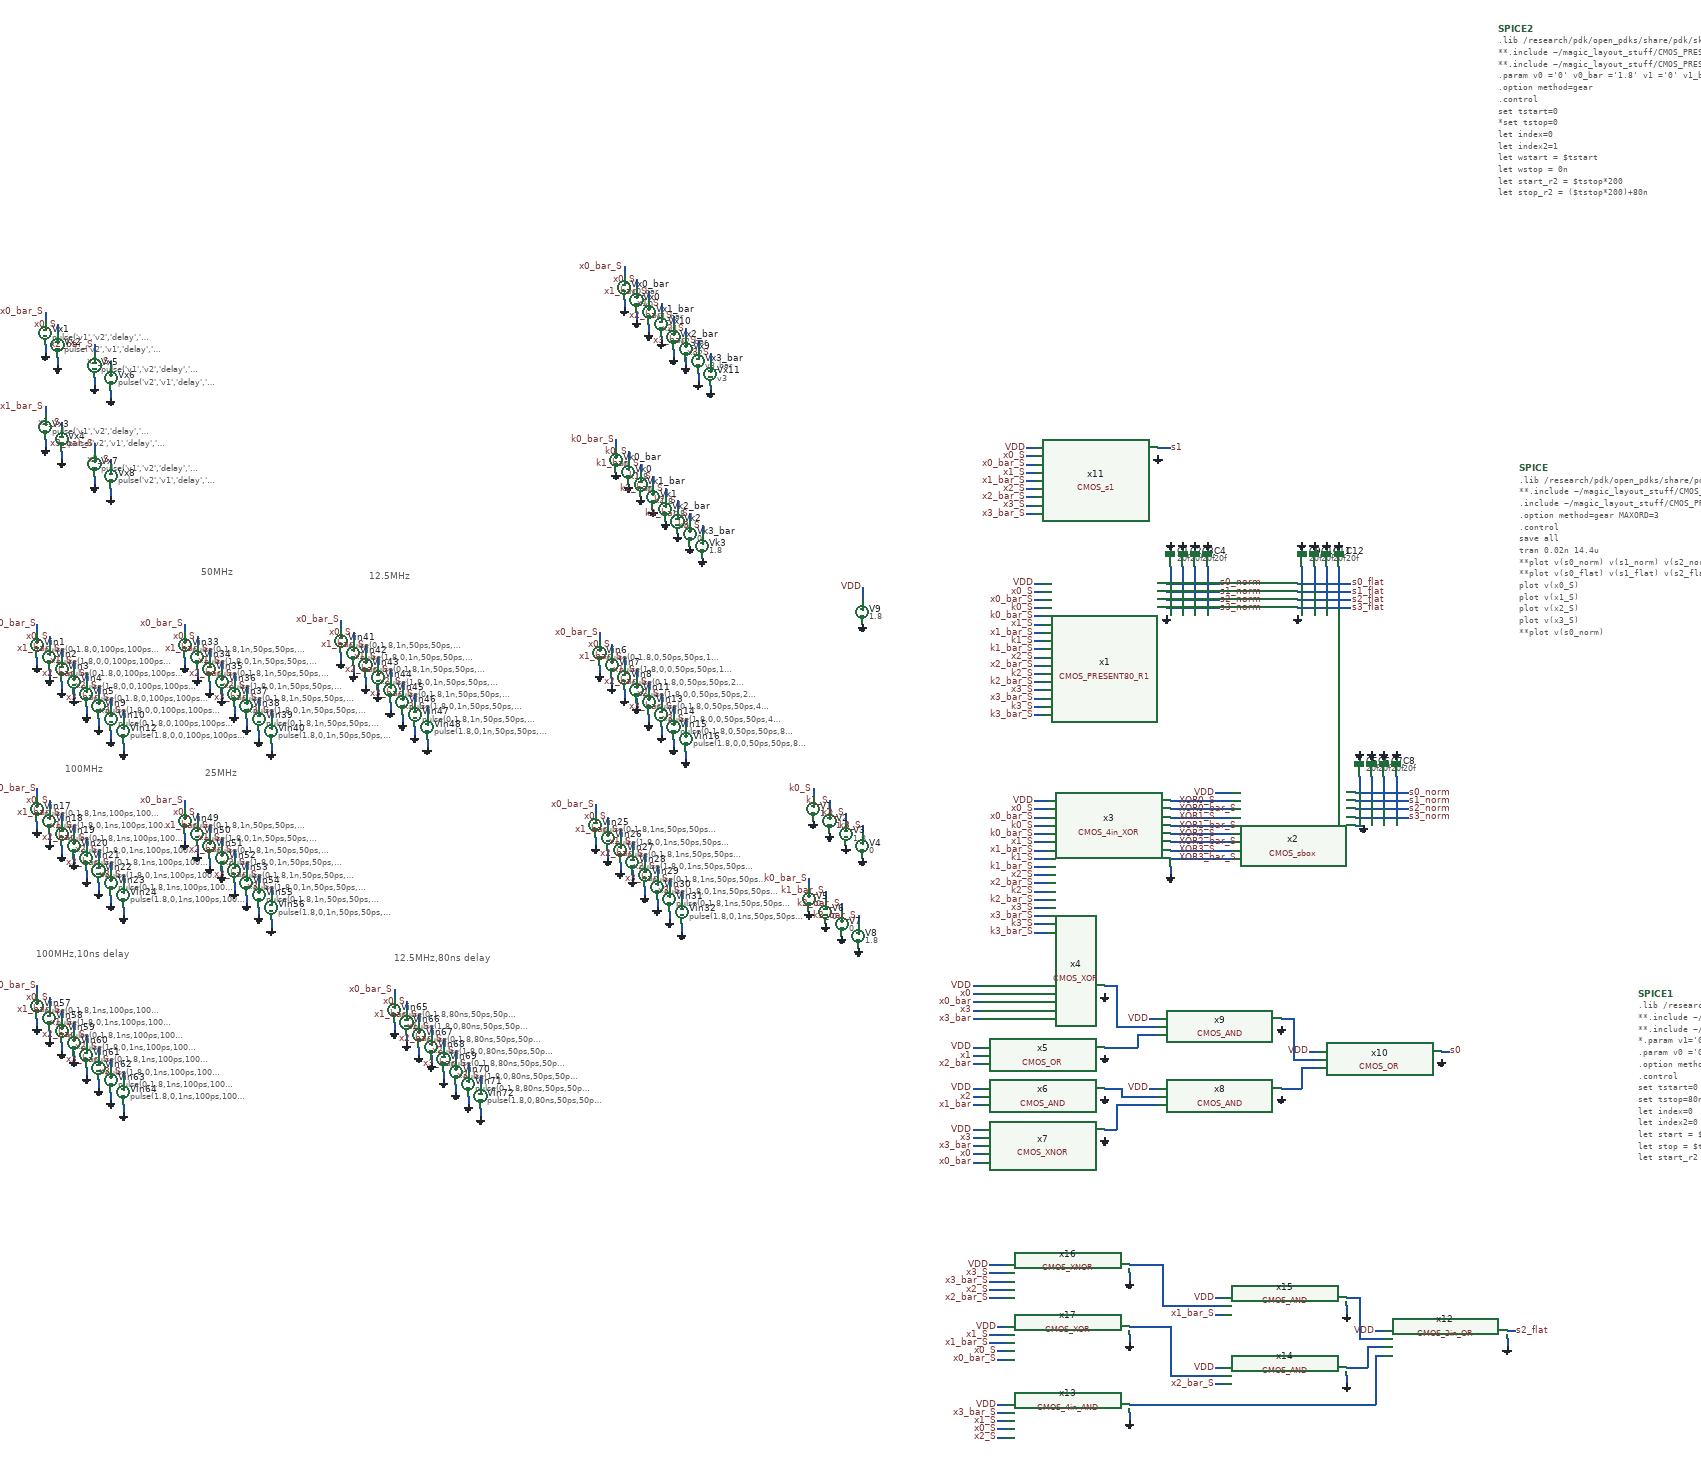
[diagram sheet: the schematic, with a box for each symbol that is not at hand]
v {xschem version=3.0.0 file_version=1.2 }
G {}
K {}
V {}
S {}
E {}
T {50MHz} -530 -1190 0 0 0.4 0.4 {}
T {25MHz} -520 -700 0 0 0.4 0.4 {}
T {12.5MHz} -120 -1180 0 0 0.4 0.4 {}
T {100MHz} -860 -710 0 0 0.4 0.4 {}
T {100MHz,10ns delay} -930 -260 0 0 0.4 0.4 {}
T {12.5MHz,80ns delay} -60 -250 0 0 0.4 0.4 {}
N 1820 -1150 1840 -1150 { lab=s0_norm}
N 1820 -1130 1840 -1130 { lab=s1_norm}
N 1820 -1110 1840 -1110 { lab=s2_norm}
N 1820 -1090 1840 -1090 { lab=s3_norm}
N 1500 -1130 1520 -1130 { lab=x0_S}
N 1500 -1110 1520 -1110 { lab=x0_bar_S}
N 1500 -890 1520 -890 { lab=x3_S}
N 1500 -870 1520 -870 { lab=x3_bar_S}
N 1500 -1050 1520 -1050 { lab=x1_S}
N 1500 -1030 1520 -1030 { lab=x1_bar_S}
N 1500 -950 1520 -950 { lab=x2_bar_S}
N 1500 -970 1520 -970 { lab=x2_S}
N 1500 -1090 1520 -1090 { lab=k0_S}
N 1500 -1070 1520 -1070 { lab=k0_bar_S}
N 1500 -1010 1520 -1010 { lab=k1_S}
N 1500 -990 1520 -990 { lab=k1_bar_S}
N 1500 -930 1520 -930 { lab=k2_S}
N 1500 -910 1520 -910 { lab=k2_bar_S}
N 1500 -850 1520 -850 { lab=k3_S}
N 1500 -830 1520 -830 { lab=k3_bar_S}
N 1500 -1150 1520 -1150 { lab=VDD}
N 1830 -1190 1830 -1150 { lab=s0_norm}
N 1840 -1150 1910 -1150 { lab=s0_norm}
N 1840 -1130 1910 -1130 { lab=s1_norm}
N 1840 -1110 1910 -1110 { lab=s2_norm}
N 1840 -1090 1910 -1090 { lab=s3_norm}
N 1910 -1150 1950 -1150 { lab=s0_norm}
N 1910 -1130 1950 -1130 { lab=s1_norm}
N 1910 -1110 1950 -1110 { lab=s2_norm}
N 1910 -1090 1950 -1090 { lab=s3_norm}
N 1860 -1190 1860 -1130 { lab=s1_norm}
N 1890 -1190 1890 -1110 { lab=s2_norm}
N 1920 -1190 1920 -1090 { lab=s3_norm}
N 1830 -620 1980 -620 { lab=#net1}
N 1830 -600 1980 -600 { lab=#net2}
N 1830 -580 1980 -580 { lab=#net3}
N 1830 -560 1980 -560 { lab=#net4}
N 1830 -540 1980 -540 { lab=#net5}
N 1830 -520 1980 -520 { lab=#net6}
N 1830 -500 1980 -500 { lab=#net7}
N 1830 -480 1980 -480 { lab=#net8}
N 1500 -600 1530 -600 { lab=x0_S}
N 1500 -580 1530 -580 { lab=x0_bar_S}
N 1500 -560 1530 -560 { lab=k0_S}
N 1500 -520 1530 -520 { lab=x1_S}
N 1500 -540 1530 -540 { lab=k0_bar_S}
N 1500 -500 1530 -500 { lab=x1_bar_S}
N 1500 -480 1530 -480 { lab=k1_S}
N 1500 -460 1530 -460 { lab=k1_bar_S}
N 1500 -440 1530 -440 { lab=x2_S}
N 1500 -420 1530 -420 { lab=x2_bar_S}
N 1500 -400 1530 -400 { lab=k2_S}
N 1500 -380 1530 -380 { lab=k2_bar_S}
N 1500 -360 1530 -360 { lab=x3_S}
N 1500 -340 1530 -340 { lab=x3_bar_S}
N 1500 -320 1530 -320 { lab=k3_S}
N 1500 -300 1530 -300 { lab=k3_bar_S}
N 2280 -560 2300 -560 { lab=GND}
N 1830 -460 1830 -440 { lab=GND}
N 1500 -620 1530 -620 { lab=VDD}
N 1940 -640 1980 -640 { lab=VDD}
N 2280 -640 2300 -640 { lab=s0_norm}
N 2280 -620 2300 -620 { lab=s1_norm}
N 2280 -600 2300 -600 { lab=s2_norm}
N 2280 -580 2300 -580 { lab=s3_norm}
N 2290 -680 2290 -640 { lab=s0_norm}
N 2300 -640 2370 -640 { lab=s0_norm}
N 2300 -620 2370 -620 { lab=s1_norm}
N 2300 -600 2370 -600 { lab=s2_norm}
N 2300 -580 2370 -580 { lab=s3_norm}
N 2370 -640 2410 -640 { lab=s0_norm}
N 2370 -620 2410 -620 { lab=s1_norm}
N 2370 -600 2410 -600 { lab=s2_norm}
N 2370 -580 2410 -580 { lab=s3_norm}
N 2320 -680 2320 -620 { lab=s1_norm}
N 2350 -680 2350 -600 { lab=s2_norm}
N 2380 -680 2380 -580 { lab=s3_norm}
N 440 -1030 440 -1010 { lab=x0_bar_S}
N 440 -950 440 -930 { lab=GND}
N 470 -1000 470 -980 { lab=x0_S}
N 470 -920 470 -900 { lab=GND}
N 500 -970 500 -950 { lab=x1_bar_S}
N 500 -890 500 -870 { lab=GND}
N 530 -940 530 -920 { lab=x1_S}
N 530 -870 530 -850 { lab=GND}
N 560 -910 560 -890 { lab=x2_bar_S}
N 560 -830 560 -810 { lab=GND}
N 590 -880 590 -860 { lab=x2_S}
N 590 -800 590 -780 { lab=GND}
N 620 -850 620 -830 { lab=x3_bar_S}
N 620 -770 620 -750 { lab=GND}
N 650 -820 650 -800 { lab=x3_S}
N 650 -740 650 -720 { lab=GND}
N 960 -650 960 -630 { lab=k0_S}
N 1040 -590 1040 -570 { lab=k2_S}
N 1080 -560 1080 -540 { lab=k3_S}
N 1000 -620 1000 -600 { lab=k1_S}
N 950 -430 950 -410 { lab=k0_bar_S}
N 1030 -370 1030 -350 { lab=k2_bar_S}
N 1070 -340 1070 -320 { lab=k3_bar_S}
N 990 -400 990 -380 { lab=k1_bar_S}
N 1080 -1140 1080 -1110 { lab=VDD}
N -930 -1050 -930 -1030 { lab=x0_bar_S}
N -930 -970 -930 -950 { lab=GND}
N -900 -1020 -900 -1000 { lab=x0_S}
N -900 -940 -900 -920 { lab=GND}
N -870 -990 -870 -970 { lab=x1_bar_S}
N -870 -910 -870 -890 { lab=GND}
N -840 -960 -840 -940 { lab=x1_S}
N -840 -890 -840 -870 { lab=GND}
N -810 -930 -810 -910 { lab=x2_bar_S}
N -810 -850 -810 -830 { lab=GND}
N -780 -900 -780 -880 { lab=x2_S}
N -780 -820 -780 -800 { lab=GND}
N -750 -870 -750 -850 { lab=x3_bar_S}
N -750 -790 -750 -770 { lab=GND}
N -720 -840 -720 -820 { lab=x3_S}
N -720 -760 -720 -740 { lab=GND}
N 1350 -150 1370 -150 { lab=x0}
N 1350 -130 1370 -130 { lab=x0_bar}
N 1350 -110 1370 -110 { lab=x3}
N 1350 -90 1370 -90 { lab=x3_bar}
N 1350 -20 1370 -20 { lab=VDD}
N 1350 0 1370 0 { lab=x1}
N 1350 20 1370 20 { lab=x2_bar}
N 1350 100 1370 100 { lab=x2}
N 1350 120 1370 120 { lab=x1_bar}
N 1350 -170 1370 -170 { lab=VDD}
N 1350 80 1370 80 { lab=VDD}
N 1350 200 1370 200 { lab=x3}
N 1350 220 1370 220 { lab=x3_bar}
N 1350 180 1370 180 { lab=VDD}
N 1350 240 1370 240 { lab=x0}
N 1350 260 1370 260 { lab=x0_bar}
N 1670 -170 1700 -170 { lab=#net1}
N 1700 -170 1700 -70 { lab=#net1}
N 1700 -70 1800 -70 { lab=#net1}
N 1670 -20 1750 -20 { lab=#net2}
N 1670 80 1710 80 { lab=#net3}
N 1710 80 1710 100 { lab=#net3}
N 1710 100 1800 100 { lab=#net3}
N 1670 180 1700 180 { lab=#net4}
N 1700 120 1700 180 { lab=#net4}
N 1700 120 1800 120 { lab=#net4}
N 1750 -50 1750 -20 { lab=#net2}
N 1750 -50 1800 -50 { lab=#net2}
N 1780 80 1800 80 { lab=VDD}
N 1780 -90 1800 -90 { lab=VDD}
N 2100 80 2150 80 { lab=#net5}
N 2150 30 2150 80 { lab=#net5}
N 2150 30 2190 30 { lab=#net5}
N 2100 -90 2130 -90 { lab=#net6}
N 2130 -90 2130 10 { lab=#net6}
N 2130 10 2190 10 { lab=#net6}
N 2490 -10 2510 -10 { lab=s0}
N 2170 -10 2190 -10 { lab=VDD}
N -930 -650 -930 -630 { lab=x0_bar_S}
N -930 -570 -930 -550 { lab=GND}
N -900 -620 -900 -600 { lab=x0_S}
N -900 -540 -900 -520 { lab=GND}
N -870 -590 -870 -570 { lab=x1_bar_S}
N -870 -510 -870 -490 { lab=GND}
N -840 -560 -840 -540 { lab=x1_S}
N -840 -490 -840 -470 { lab=GND}
N -810 -530 -810 -510 { lab=x2_bar_S}
N -810 -450 -810 -430 { lab=GND}
N -780 -500 -780 -480 { lab=x2_S}
N -780 -420 -780 -400 { lab=GND}
N -750 -470 -750 -450 { lab=x3_bar_S}
N -750 -390 -750 -370 { lab=GND}
N -720 -440 -720 -420 { lab=x3_S}
N -720 -360 -720 -340 { lab=GND}
N 430 -610 430 -590 { lab=x0_bar_S}
N 430 -530 430 -510 { lab=GND}
N 460 -580 460 -560 { lab=x0_S}
N 460 -500 460 -480 { lab=GND}
N 490 -550 490 -530 { lab=x1_bar_S}
N 490 -470 490 -450 { lab=GND}
N 520 -520 520 -500 { lab=x1_S}
N 520 -450 520 -430 { lab=GND}
N 550 -490 550 -470 { lab=x2_bar_S}
N 550 -410 550 -390 { lab=GND}
N 580 -460 580 -440 { lab=x2_S}
N 580 -380 580 -360 { lab=GND}
N 610 -430 610 -410 { lab=x3_bar_S}
N 610 -350 610 -330 { lab=GND}
N 640 -400 640 -380 { lab=x3_S}
N 640 -320 640 -300 { lab=GND}
N 1480 -1460 1500 -1460 { lab=x0_S}
N 1480 -1440 1500 -1440 { lab=x0_bar_S}
N 1480 -1340 1500 -1340 { lab=x3_S}
N 1480 -1320 1500 -1320 { lab=x3_bar_S}
N 1480 -1420 1500 -1420 { lab=x1_S}
N 1480 -1400 1500 -1400 { lab=x1_bar_S}
N 1480 -1360 1500 -1360 { lab=x2_bar_S}
N 1480 -1380 1500 -1380 { lab=x2_S}
N 1480 -1480 1500 -1480 { lab=VDD}
N 1800 -1480 1830 -1480 { lab=s1}
N 1390 530 1410 530 { lab=x3_S}
N 1390 550 1410 550 { lab=x3_bar_S}
N 1390 680 1410 680 { lab=x1_S}
N 1390 590 1410 590 { lab=x2_bar_S}
N 1390 570 1410 570 { lab=x2_S}
N 1390 700 1410 700 { lab=x1_bar_S}
N 1410 530 1430 530 { lab=x3_S}
N 1410 550 1430 550 { lab=x3_bar_S}
N 1410 720 1430 720 { lab=x0_S}
N 1410 740 1430 740 { lab=x0_bar_S}
N 1410 660 1430 660 { lab=VDD}
N 1410 680 1430 680 { lab=x1_S}
N 1410 590 1430 590 { lab=x2_bar_S}
N 1410 570 1430 570 { lab=x2_S}
N 1410 700 1430 700 { lab=x1_bar_S}
N 1410 510 1430 510 { lab=VDD}
N 1410 870 1430 870 { lab=x3_bar_S}
N 1410 850 1430 850 { lab=VDD}
N 1410 910 1430 910 { lab=x0_S}
N 1940 760 1960 760 { lab=VDD}
N 1940 590 1960 590 { lab=VDD}
N 2260 760 2310 760 { lab=#net1}
N 2310 710 2310 760 { lab=#net1}
N 2310 710 2350 710 { lab=#net1}
N 2260 590 2290 590 { lab=#net2}
N 2290 590 2290 690 { lab=#net2}
N 2290 690 2350 690 { lab=#net2}
N 2650 670 2670 670 { lab=s2_flat}
N 2330 670 2350 670 { lab=VDD}
N 1410 890 1430 890 { lab=x1_S}
N 1730 510 1810 510 { lab=#net3}
N 1810 510 1810 610 { lab=#net3}
N 1810 610 1960 610 { lab=#net3}
N 1940 630 1960 630 { lab=x1_bar_S}
N 1730 660 1830 660 { lab=#net4}
N 1830 660 1830 780 { lab=#net4}
N 1830 780 1960 780 { lab=#net4}
N 1940 800 1960 800 { lab=x2_bar_S}
N 1730 850 2330 850 { lab=#net5}
N 2330 730 2330 850 { lab=#net5}
N 2330 730 2350 730 { lab=#net5}
N 1410 930 1430 930 { lab=x2_S}
N 1730 680 1730 700 { lab=GND}
N 2650 690 2650 710 { lab=GND}
N 1730 530 1730 550 { lab=GND}
N 1730 870 1730 890 { lab=GND}
N 2260 610 2260 630 { lab=GND}
N 2260 780 2260 800 { lab=GND}
N 1390 510 1410 510 { lab=VDD}
N -570 -1050 -570 -1030 { lab=x0_bar_S}
N -570 -970 -570 -950 { lab=GND}
N -540 -1020 -540 -1000 { lab=x0_S}
N -540 -940 -540 -920 { lab=GND}
N -510 -990 -510 -970 { lab=x1_bar_S}
N -510 -910 -510 -890 { lab=GND}
N -480 -960 -480 -940 { lab=x1_S}
N -480 -890 -480 -870 { lab=GND}
N -450 -930 -450 -910 { lab=x2_bar_S}
N -450 -850 -450 -830 { lab=GND}
N -420 -900 -420 -880 { lab=x2_S}
N -420 -820 -420 -800 { lab=GND}
N -390 -870 -390 -850 { lab=x3_bar_S}
N -390 -790 -390 -770 { lab=GND}
N -360 -840 -360 -820 { lab=x3_S}
N -360 -760 -360 -740 { lab=GND}
N -190 -1060 -190 -1040 { lab=x0_bar_S}
N -190 -980 -190 -960 { lab=GND}
N -160 -1030 -160 -1010 { lab=x0_S}
N -160 -950 -160 -930 { lab=GND}
N -130 -1000 -130 -980 { lab=x1_bar_S}
N -130 -920 -130 -900 { lab=GND}
N -100 -970 -100 -950 { lab=x1_S}
N -100 -900 -100 -880 { lab=GND}
N -70 -940 -70 -920 { lab=x2_bar_S}
N -70 -860 -70 -840 { lab=GND}
N -40 -910 -40 -890 { lab=x2_S}
N -40 -830 -40 -810 { lab=GND}
N -10 -880 -10 -860 { lab=x3_bar_S}
N -10 -800 -10 -780 { lab=GND}
N 20 -850 20 -830 { lab=x3_S}
N 20 -770 20 -750 { lab=GND}
N -570 -620 -570 -600 { lab=x0_bar_S}
N -570 -540 -570 -520 { lab=GND}
N -540 -590 -540 -570 { lab=x0_S}
N -540 -510 -540 -490 { lab=GND}
N -510 -560 -510 -540 { lab=x1_bar_S}
N -510 -480 -510 -460 { lab=GND}
N -480 -530 -480 -510 { lab=x1_S}
N -480 -460 -480 -440 { lab=GND}
N -450 -500 -450 -480 { lab=x2_bar_S}
N -450 -420 -450 -400 { lab=GND}
N -420 -470 -420 -450 { lab=x2_S}
N -420 -390 -420 -370 { lab=GND}
N -390 -440 -390 -420 { lab=x3_bar_S}
N -390 -360 -390 -340 { lab=GND}
N -360 -410 -360 -390 { lab=x3_S}
N -360 -330 -360 -310 { lab=GND}
N -930 -170 -930 -150 { lab=x0_bar_S}
N -930 -90 -930 -70 { lab=GND}
N -900 -140 -900 -120 { lab=x0_S}
N -900 -60 -900 -40 { lab=GND}
N -870 -110 -870 -90 { lab=x1_bar_S}
N -870 -30 -870 -10 { lab=GND}
N -840 -80 -840 -60 { lab=x1_S}
N -840 -10 -840 10 { lab=GND}
N -810 -50 -810 -30 { lab=x2_bar_S}
N -810 30 -810 50 { lab=GND}
N -780 -20 -780 0 { lab=x2_S}
N -780 60 -780 80 { lab=GND}
N -750 10 -750 30 { lab=x3_bar_S}
N -750 90 -750 110 { lab=GND}
N -720 40 -720 60 { lab=x3_S}
N -720 120 -720 140 { lab=GND}
N -60 -160 -60 -140 { lab=x0_bar_S}
N -60 -80 -60 -60 { lab=GND}
N -30 -130 -30 -110 { lab=x0_S}
N -30 -50 -30 -30 { lab=GND}
N 0 -100 0 -80 { lab=x1_bar_S}
N 0 -20 0 0 { lab=GND}
N 30 -70 30 -50 { lab=x1_S}
N 30 0 30 20 { lab=GND}
N 60 -40 60 -20 { lab=x2_bar_S}
N 60 40 60 60 { lab=GND}
N 90 -10 90 10 { lab=x2_S}
N 90 70 90 90 { lab=GND}
N 120 20 120 40 { lab=x3_bar_S}
N 120 100 120 120 { lab=GND}
N 150 50 150 70 { lab=x3_S}
N 150 130 150 150 { lab=GND}
N 2140 -1150 2160 -1150 { lab=s0_flat}
N 2140 -1130 2160 -1130 { lab=s1_flat}
N 2140 -1110 2160 -1110 { lab=s2_flat}
N 2140 -1090 2160 -1090 { lab=s3_flat}
N 2150 -1190 2150 -1150 { lab=s0_flat}
N 2160 -1150 2230 -1150 { lab=s0_flat}
N 2160 -1130 2230 -1130 { lab=s1_flat}
N 2160 -1110 2230 -1110 { lab=s2_flat}
N 2160 -1090 2230 -1090 { lab=s3_flat}
N 2230 -1150 2270 -1150 { lab=s0_flat}
N 2230 -1130 2270 -1130 { lab=s1_flat}
N 2230 -1110 2270 -1110 { lab=s2_flat}
N 2230 -1090 2270 -1090 { lab=s3_flat}
N 2180 -1190 2180 -1130 { lab=s1_flat}
N 2210 -1190 2210 -1110 { lab=s2_flat}
N 2240 -1190 2240 -1090 { lab=s3_flat}
N -910 -1580 -910 -1560 { lab=x1_bar_S}
N -870 -1540 -870 -1520 { lab=x1_S}
N -910 -1810 -910 -1790 { lab=x0_bar_S}
N -910 -1730 -910 -1710 { lab=GND}
N -880 -1780 -880 -1760 { lab=x0_S}
N -880 -1700 -880 -1680 { lab=GND}
N -910 -1500 -910 -1480 { lab=GND}
N -870 -1470 -870 -1450 { lab=GND}
N -790 -1730 -790 -1710 { lab=x2_bar_S}
N -750 -1690 -750 -1670 { lab=x2_S}
N -790 -1650 -790 -1630 { lab=GND}
N -750 -1620 -750 -1600 { lab=GND}
N -790 -1490 -790 -1470 { lab=x3_bar_S}
N -750 -1450 -750 -1430 { lab=x3_S}
N -790 -1410 -790 -1390 { lab=GND}
N -750 -1380 -750 -1360 { lab=GND}
N 510 -1470 510 -1450 { lab=k0_S}
N 630 -1350 630 -1330 { lab=k2_S}
N 690 -1290 690 -1270 { lab=k3_S}
N 570 -1410 570 -1390 { lab=k1_S}
N 480 -1500 480 -1480 { lab=k0_bar_S}
N 600 -1380 600 -1360 { lab=k2_bar_S}
N 660 -1320 660 -1300 { lab=k3_bar_S}
N 540 -1440 540 -1420 { lab=k1_bar_S}
N 560 -1860 560 -1840 { lab=x1_bar_S}
N 590 -1830 590 -1810 { lab=x1_S}
N 500 -1920 500 -1900 { lab=x0_bar_S}
N 500 -1840 500 -1820 { lab=GND}
N 530 -1890 530 -1870 { lab=x0_S}
N 530 -1810 530 -1790 { lab=GND}
N 560 -1780 560 -1760 { lab=GND}
N 620 -1800 620 -1780 { lab=x2_bar_S}
N 650 -1770 650 -1750 { lab=x2_S}
N 620 -1720 620 -1700 { lab=GND}
N 650 -1700 650 -1680 { lab=GND}
N 680 -1740 680 -1720 { lab=x3_bar_S}
N 710 -1710 710 -1690 { lab=x3_S}
N 680 -1660 680 -1640 { lab=GND}
N 590 -1750 590 -1740 { lab=GND}
N 710 -1630 710 -1620 { lab=GND}
C {CMOS_PRESENT80_R1.sym} 1670 -990 0 0 {name=x1}
C {devices/gnd.sym} 1820 -1070 0 0 {name=l314 lab=GND}
C {devices/lab_pin.sym} 1950 -1150 2 0 {name=l315 sig_type=std_logic lab=s0_norm}
C {devices/lab_pin.sym} 1950 -1130 2 0 {name=l317 sig_type=std_logic lab=s1_norm}
C {devices/lab_pin.sym} 1950 -1110 2 0 {name=l319 sig_type=std_logic lab=s2_norm}
C {devices/lab_pin.sym} 1950 -1090 2 0 {name=l321 sig_type=std_logic lab=s3_norm}
C {devices/lab_pin.sym} 1500 -1130 0 0 {name=l323 sig_type=std_logic lab=x0_S}
C {devices/lab_pin.sym} 1500 -1110 0 0 {name=l324 sig_type=std_logic lab=x0_bar_S}
C {devices/lab_pin.sym} 1500 -890 0 0 {name=l325 sig_type=std_logic lab=x3_S}
C {devices/lab_pin.sym} 1500 -870 0 0 {name=l326 sig_type=std_logic lab=x3_bar_S}
C {devices/lab_pin.sym} 1500 -1030 0 0 {name=l328 sig_type=std_logic lab=x1_bar_S}
C {devices/lab_pin.sym} 1500 -1050 0 0 {name=l329 sig_type=std_logic lab=x1_S}
C {devices/lab_pin.sym} 1500 -950 0 0 {name=l330 sig_type=std_logic lab=x2_bar_S}
C {devices/lab_pin.sym} 1500 -970 0 0 {name=l331 sig_type=std_logic lab=x2_S}
C {devices/lab_pin.sym} 1500 -1090 0 0 {name=l332 sig_type=std_logic lab=k0_S}
C {devices/lab_pin.sym} 1500 -1010 0 0 {name=l333 sig_type=std_logic lab=k1_S}
C {devices/lab_pin.sym} 1500 -930 0 0 {name=l334 sig_type=std_logic lab=k2_S}
C {devices/lab_pin.sym} 1500 -850 0 0 {name=l335 sig_type=std_logic lab=k3_S}
C {devices/lab_pin.sym} 1500 -1070 0 0 {name=l336 sig_type=std_logic lab=k0_bar_S}
C {devices/lab_pin.sym} 1500 -990 0 0 {name=l337 sig_type=std_logic lab=k1_bar_S}
C {devices/lab_pin.sym} 1500 -910 0 0 {name=l338 sig_type=std_logic lab=k2_bar_S}
C {devices/lab_pin.sym} 1500 -830 0 0 {name=l339 sig_type=std_logic lab=k3_bar_S}
C {devices/lab_pin.sym} 1500 -1150 0 0 {name=l1 sig_type=std_logic lab=VDD}
C {devices/capa.sym} 1830 -1220 2 0 {name=C1
m=1
value=20f
footprint=1206
device="ceramic capacitor"}
C {devices/gnd.sym} 1830 -1250 2 0 {name=l4 lab=GND}
C {devices/capa.sym} 1860 -1220 2 0 {name=C2
m=1
value=20f
footprint=1206
device="ceramic capacitor"}
C {devices/gnd.sym} 1860 -1250 2 0 {name=l5 lab=GND}
C {devices/capa.sym} 1890 -1220 2 0 {name=C3
m=1
value=20f
footprint=1206
device="ceramic capacitor"}
C {devices/gnd.sym} 1890 -1250 2 0 {name=l6 lab=GND}
C {devices/capa.sym} 1920 -1220 2 0 {name=C4
m=1
value=20f
footprint=1206
device="ceramic capacitor"}
C {devices/gnd.sym} 1920 -1250 2 0 {name=l7 lab=GND}
C {devices/lab_pin.sym} 1940 -640 0 0 {name=l8 sig_type=std_logic lab=VDD}
C {CMOS_sbox.sym} 2130 -560 0 0 {name=x2}
C {CMOS_4in_XOR.sym} 1680 -460 0 0 {name=x3}
C {devices/lab_pin.sym} 1500 -600 0 0 {name=l21 sig_type=std_logic lab=x0_S}
C {devices/lab_pin.sym} 1500 -580 0 0 {name=l22 sig_type=std_logic lab=x0_bar_S}
C {devices/lab_pin.sym} 1500 -360 0 0 {name=l25 sig_type=std_logic lab=x3_S}
C {devices/lab_pin.sym} 1500 -340 0 0 {name=l26 sig_type=std_logic lab=x3_bar_S}
C {devices/lab_pin.sym} 1500 -500 0 0 {name=l27 sig_type=std_logic lab=x1_bar_S}
C {devices/lab_pin.sym} 1500 -520 0 0 {name=l28 sig_type=std_logic lab=x1_S}
C {devices/lab_pin.sym} 1500 -420 0 0 {name=l29 sig_type=std_logic lab=x2_bar_S}
C {devices/lab_pin.sym} 1500 -440 0 0 {name=l30 sig_type=std_logic lab=x2_S}
C {devices/lab_pin.sym} 1500 -560 0 0 {name=l34 sig_type=std_logic lab=k0_S}
C {devices/lab_pin.sym} 1500 -480 0 0 {name=l35 sig_type=std_logic lab=k1_S}
C {devices/lab_pin.sym} 1500 -400 0 0 {name=l36 sig_type=std_logic lab=k2_S}
C {devices/lab_pin.sym} 1500 -320 0 0 {name=l37 sig_type=std_logic lab=k3_S}
C {devices/lab_pin.sym} 1500 -540 0 0 {name=l38 sig_type=std_logic lab=k0_bar_S}
C {devices/lab_pin.sym} 1500 -460 0 0 {name=l39 sig_type=std_logic lab=k1_bar_S}
C {devices/lab_pin.sym} 1500 -380 0 0 {name=l40 sig_type=std_logic lab=k2_bar_S}
C {devices/lab_pin.sym} 1500 -300 0 0 {name=l41 sig_type=std_logic lab=k3_bar_S}
C {devices/lab_pin.sym} 1500 -620 0 0 {name=l42 sig_type=std_logic lab=VDD}
C {devices/gnd.sym} 2300 -560 0 0 {name=l47 lab=GND}
C {devices/gnd.sym} 1830 -440 0 0 {name=l20 lab=GND}
C {devices/lab_pin.sym} 2410 -640 2 0 {name=l43 sig_type=std_logic lab=s0_norm}
C {devices/lab_pin.sym} 2410 -620 2 0 {name=l44 sig_type=std_logic lab=s1_norm}
C {devices/lab_pin.sym} 2410 -600 2 0 {name=l45 sig_type=std_logic lab=s2_norm}
C {devices/lab_pin.sym} 2410 -580 2 0 {name=l46 sig_type=std_logic lab=s3_norm}
C {devices/capa.sym} 2290 -710 2 0 {name=C5
m=1
value=20f
footprint=1206
device="ceramic capacitor"}
C {devices/gnd.sym} 2290 -740 2 0 {name=l48 lab=GND}
C {devices/capa.sym} 2320 -710 2 0 {name=C6
m=1
value=20f
footprint=1206
device="ceramic capacitor"}
C {devices/gnd.sym} 2320 -740 2 0 {name=l49 lab=GND}
C {devices/capa.sym} 2350 -710 2 0 {name=C7
m=1
value=20f
footprint=1206
device="ceramic capacitor"}
C {devices/gnd.sym} 2350 -740 2 0 {name=l50 lab=GND}
C {devices/capa.sym} 2380 -710 2 0 {name=C8
m=1
value=20f
footprint=1206
device="ceramic capacitor"}
C {devices/gnd.sym} 2380 -740 2 0 {name=l51 lab=GND}
C {devices/lab_pin.sym} 1850 -600 2 0 {name=l210 sig_type=std_logic lab=XOR0_bar_S}
C {devices/lab_pin.sym} 1850 -620 2 0 {name=l211 sig_type=std_logic lab=XOR0_S}
C {devices/lab_pin.sym} 1850 -560 2 0 {name=l222 sig_type=std_logic lab=XOR1_bar_S}
C {devices/lab_pin.sym} 1850 -580 2 0 {name=l223 sig_type=std_logic lab=XOR1_S}
C {devices/lab_pin.sym} 1850 -520 2 0 {name=l224 sig_type=std_logic lab=XOR2_bar_S}
C {devices/lab_pin.sym} 1850 -540 2 0 {name=l225 sig_type=std_logic lab=XOR2_S}
C {devices/lab_pin.sym} 1850 -480 2 0 {name=l226 sig_type=std_logic lab=XOR3_bar_S}
C {devices/lab_pin.sym} 1850 -500 2 0 {name=l227 sig_type=std_logic lab=XOR3_S}
C {devices/gnd.sym} 560 -810 0 0 {name=l102 lab=GND}
C {devices/lab_pin.sym} 590 -880 1 0 {name=l103 sig_type=std_logic lab=x2_S}
C {devices/lab_pin.sym} 620 -850 1 0 {name=l104 sig_type=std_logic lab=x3_bar_S}
C {devices/gnd.sym} 650 -720 0 0 {name=l105 lab=GND}
C {devices/gnd.sym} 620 -750 0 0 {name=l106 lab=GND}
C {devices/lab_pin.sym} 650 -820 1 0 {name=l107 sig_type=std_logic lab=x3_S}
C {devices/vsource.sym} 440 -980 0 0 {name=Vin6 value=pulse(0,1.8,0,50ps,50ps,100ns,200ns)}
C {devices/vsource.sym} 470 -950 0 0 {name=Vin7 value=pulse(1.8,0,0,50ps,50ps,100ns,200ns)}
C {devices/vsource.sym} 500 -920 0 0 {name=Vin8 value=pulse(0,1.8,0,50ps,50ps,200ns,400ns)}
C {devices/vsource.sym} 530 -890 0 0 {name=Vin11 value=pulse(1.8,0,0,50ps,50ps,200ns,400ns)}
C {devices/vsource.sym} 560 -860 0 0 {name=Vin13 value=pulse(0,1.8,0,50ps,50ps,400ns,800ns)}
C {devices/vsource.sym} 590 -830 0 0 {name=Vin14 value=pulse(1.8,0,0,50ps,50ps,400ns,800ns)}
C {devices/vsource.sym} 620 -800 0 0 {name=Vin15 value=pulse(0,1.8,0,50ps,50ps,800ns,1600ns)}
C {devices/vsource.sym} 650 -770 0 0 {name=Vin16 value=pulse(1.8,0,0,50ps,50ps,800ns,1600ns)}
C {devices/lab_pin.sym} 440 -1030 1 0 {name=l124 sig_type=std_logic lab=x0_bar_S}
C {devices/gnd.sym} 470 -900 0 0 {name=l125 lab=GND}
C {devices/gnd.sym} 440 -930 0 0 {name=l126 lab=GND}
C {devices/lab_pin.sym} 470 -1000 1 0 {name=l127 sig_type=std_logic lab=x0_S}
C {devices/lab_pin.sym} 500 -970 1 0 {name=l128 sig_type=std_logic lab=x1_bar_S}
C {devices/gnd.sym} 530 -850 0 0 {name=l129 lab=GND}
C {devices/gnd.sym} 500 -870 0 0 {name=l130 lab=GND}
C {devices/lab_pin.sym} 530 -940 1 0 {name=l131 sig_type=std_logic lab=x1_S}
C {devices/lab_pin.sym} 560 -910 1 0 {name=l132 sig_type=std_logic lab=x2_bar_S}
C {devices/gnd.sym} 590 -780 0 0 {name=l133 lab=GND}
C {devices/vsource.sym} 960 -600 0 0 {name=V1 value=1.8}
C {devices/vsource.sym} 1000 -570 0 0 {name=V2 value=1.8}
C {devices/vsource.sym} 1040 -540 0 0 {name=V3 value=1.8}
C {devices/vsource.sym} 1080 -510 0 0 {name=V4 value=0}
C {devices/gnd.sym} 960 -570 0 0 {name=l9 lab=GND}
C {devices/gnd.sym} 1000 -540 0 0 {name=l10 lab=GND}
C {devices/gnd.sym} 1040 -510 0 0 {name=l11 lab=GND}
C {devices/gnd.sym} 1080 -480 0 0 {name=l12 lab=GND}
C {devices/lab_pin.sym} 960 -650 1 0 {name=l13 sig_type=std_logic lab=k0_S}
C {devices/lab_pin.sym} 1000 -620 1 0 {name=l14 sig_type=std_logic lab=k1_S}
C {devices/lab_pin.sym} 1040 -590 1 0 {name=l15 sig_type=std_logic lab=k2_S}
C {devices/lab_pin.sym} 1080 -560 1 0 {name=l16 sig_type=std_logic lab=k3_S}
C {devices/vsource.sym} 950 -380 0 0 {name=V5 value=0}
C {devices/vsource.sym} 990 -350 0 0 {name=V6 value=0}
C {devices/vsource.sym} 1030 -320 0 0 {name=V7 value=0}
C {devices/vsource.sym} 1070 -290 0 0 {name=V8 value=1.8}
C {devices/gnd.sym} 950 -350 0 0 {name=l17 lab=GND}
C {devices/gnd.sym} 990 -320 0 0 {name=l18 lab=GND}
C {devices/gnd.sym} 1030 -290 0 0 {name=l19 lab=GND}
C {devices/gnd.sym} 1070 -260 0 0 {name=l23 lab=GND}
C {devices/lab_pin.sym} 950 -430 1 0 {name=l24 sig_type=std_logic lab=k0_bar_S}
C {devices/lab_pin.sym} 990 -400 1 0 {name=l31 sig_type=std_logic lab=k1_bar_S}
C {devices/lab_pin.sym} 1030 -370 1 0 {name=l32 sig_type=std_logic lab=k2_bar_S}
C {devices/lab_pin.sym} 1070 -340 1 0 {name=l33 sig_type=std_logic lab=k3_bar_S}
C {devices/vsource.sym} 1080 -1080 0 0 {name=V9 value=1.8}
C {devices/gnd.sym} 1080 -1050 0 0 {name=l2 lab=GND}
C {devices/lab_pin.sym} 1080 -1140 1 0 {name=l3 sig_type=std_logic lab=VDD}
C {devices/gnd.sym} -810 -830 0 0 {name=l52 lab=GND}
C {devices/lab_pin.sym} -780 -900 1 0 {name=l53 sig_type=std_logic lab=x2_S}
C {devices/lab_pin.sym} -750 -870 1 0 {name=l54 sig_type=std_logic lab=x3_bar_S}
C {devices/gnd.sym} -720 -740 0 0 {name=l55 lab=GND}
C {devices/gnd.sym} -750 -770 0 0 {name=l56 lab=GND}
C {devices/lab_pin.sym} -720 -840 1 0 {name=l57 sig_type=std_logic lab=x3_S}
C {devices/vsource.sym} -930 -1000 0 0 {name=Vin1 value=pulse(0,1.8,0,100ps,100ps,10ns,20ns)}
C {devices/vsource.sym} -900 -970 0 0 {name=Vin2 value=pulse(1.8,0,0,100ps,100ps,10ns,20ns)}
C {devices/vsource.sym} -870 -940 0 0 {name=Vin3 value=pulse(0,1.8,0,100ps,100ps,20ns,40ns)}
C {devices/vsource.sym} -840 -910 0 0 {name=Vin4 value=pulse(1.8,0,0,100ps,100ps,20ns,40ns)}
C {devices/vsource.sym} -810 -880 0 0 {name=Vin5 value=pulse(0,1.8,0,100ps,100ps,40ns,80ns)}
C {devices/vsource.sym} -780 -850 0 0 {name=Vin9 value=pulse(1.8,0,0,100ps,100ps,40ns,80ns)}
C {devices/vsource.sym} -750 -820 0 0 {name=Vin10 value=pulse(0,1.8,0,100ps,100ps,80ns,160ns)}
C {devices/vsource.sym} -720 -790 0 0 {name=Vin12 value=pulse(1.8,0,0,100ps,100ps,80ns,160ns)}
C {devices/lab_pin.sym} -930 -1050 1 0 {name=l58 sig_type=std_logic lab=x0_bar_S}
C {devices/gnd.sym} -900 -920 0 0 {name=l59 lab=GND}
C {devices/gnd.sym} -930 -950 0 0 {name=l60 lab=GND}
C {devices/lab_pin.sym} -900 -1020 1 0 {name=l61 sig_type=std_logic lab=x0_S}
C {devices/lab_pin.sym} -870 -990 1 0 {name=l62 sig_type=std_logic lab=x1_bar_S}
C {devices/gnd.sym} -840 -870 0 0 {name=l63 lab=GND}
C {devices/gnd.sym} -870 -890 0 0 {name=l64 lab=GND}
C {devices/lab_pin.sym} -840 -960 1 0 {name=l65 sig_type=std_logic lab=x1_S}
C {devices/lab_pin.sym} -810 -930 1 0 {name=l66 sig_type=std_logic lab=x2_bar_S}
C {devices/gnd.sym} -780 -800 0 0 {name=l67 lab=GND}
C {devices/lab_pin.sym} 1350 -150 0 0 {name=l68 sig_type=std_logic lab=x0}
C {devices/lab_pin.sym} 1350 -130 0 0 {name=l69 sig_type=std_logic lab=x0_bar}
C {devices/lab_pin.sym} 1350 -110 0 0 {name=l70 sig_type=std_logic lab=x3}
C {devices/lab_pin.sym} 1350 -90 0 0 {name=l71 sig_type=std_logic lab=x3_bar}
C {devices/lab_pin.sym} 1350 0 0 0 {name=l72 sig_type=std_logic lab=x1}
C {devices/lab_pin.sym} 1350 20 0 0 {name=l73 sig_type=std_logic lab=x2_bar}
C {devices/lab_pin.sym} 1350 120 0 0 {name=l74 sig_type=std_logic lab=x1_bar}
C {devices/lab_pin.sym} 1350 100 0 0 {name=l75 sig_type=std_logic lab=x2}
C {devices/gnd.sym} 1670 -150 0 0 {name=l76 lab=GND}
C {CMOS_XOR.sym} 1520 -130 0 0 {name=x4}
C {devices/lab_pin.sym} 1350 -170 0 0 {name=l77 sig_type=std_logic lab=VDD}
C {CMOS_OR.sym} 1520 0 0 0 {name=x5}
C {devices/lab_pin.sym} 1350 -20 0 0 {name=l78 sig_type=std_logic lab=VDD}
C {CMOS_AND.sym} 1520 100 0 0 {name=x6}
C {devices/lab_pin.sym} 1350 80 0 0 {name=l79 sig_type=std_logic lab=VDD}
C {devices/lab_pin.sym} 1350 200 0 0 {name=l80 sig_type=std_logic lab=x3}
C {devices/lab_pin.sym} 1350 220 0 0 {name=l81 sig_type=std_logic lab=x3_bar}
C {devices/lab_pin.sym} 1350 180 0 0 {name=l82 sig_type=std_logic lab=VDD}
C {devices/lab_pin.sym} 1350 240 0 0 {name=l83 sig_type=std_logic lab=x0}
C {devices/lab_pin.sym} 1350 260 0 0 {name=l84 sig_type=std_logic lab=x0_bar}
C {devices/gnd.sym} 1670 0 0 0 {name=l85 lab=GND}
C {devices/gnd.sym} 1670 100 0 0 {name=l86 lab=GND}
C {devices/gnd.sym} 1670 200 0 0 {name=l87 lab=GND}
C {CMOS_XNOR.sym} 1520 220 0 0 {name=x7}
C {CMOS_AND.sym} 1950 100 0 0 {name=x8}
C {CMOS_AND.sym} 1950 -70 0 0 {name=x9}
C {CMOS_OR.sym} 2340 10 0 0 {name=x10}
C {devices/gnd.sym} 2100 -70 0 0 {name=l88 lab=GND}
C {devices/gnd.sym} 2100 100 0 0 {name=l89 lab=GND}
C {devices/gnd.sym} 2490 10 0 0 {name=l90 lab=GND}
C {devices/lab_pin.sym} 1780 -90 0 0 {name=l91 sig_type=std_logic lab=VDD}
C {devices/lab_pin.sym} 2170 -10 0 0 {name=l92 sig_type=std_logic lab=VDD}
C {devices/lab_pin.sym} 2510 -10 2 0 {name=l93 sig_type=std_logic lab=s0}
C {devices/lab_pin.sym} 1780 80 0 0 {name=l94 sig_type=std_logic lab=VDD}
C {devices/gnd.sym} -810 -430 0 0 {name=l95 lab=GND}
C {devices/lab_pin.sym} -780 -500 1 0 {name=l96 sig_type=std_logic lab=x2_S}
C {devices/lab_pin.sym} -750 -470 1 0 {name=l97 sig_type=std_logic lab=x3_bar_S}
C {devices/gnd.sym} -720 -340 0 0 {name=l98 lab=GND}
C {devices/gnd.sym} -750 -370 0 0 {name=l99 lab=GND}
C {devices/lab_pin.sym} -720 -440 1 0 {name=l100 sig_type=std_logic lab=x3_S}
C {devices/vsource.sym} -930 -600 0 0 {name=Vin17 value=pulse(0,1.8,1ns,100ps,100ps,10ns,20ns)}
C {devices/vsource.sym} -900 -570 0 0 {name=Vin18 value=pulse(1.8,0,1ns,100ps,100ps,10ns,20ns)}
C {devices/vsource.sym} -870 -540 0 0 {name=Vin19 value=pulse(0,1.8,1ns,100ps,100ps,20ns,40ns)}
C {devices/vsource.sym} -840 -510 0 0 {name=Vin20 value=pulse(1.8,0,1ns,100ps,100ps,20ns,40ns)}
C {devices/vsource.sym} -810 -480 0 0 {name=Vin21 value=pulse(0,1.8,1ns,100ps,100ps,40ns,80ns)}
C {devices/vsource.sym} -780 -450 0 0 {name=Vin22 value=pulse(1.8,0,1ns,100ps,100ps,40ns,80ns)}
C {devices/vsource.sym} -750 -420 0 0 {name=Vin23 value=pulse(0,1.8,1ns,100ps,100ps,80ns,160ns)}
C {devices/vsource.sym} -720 -390 0 0 {name=Vin24 value=pulse(1.8,0,1ns,100ps,100ps,80ns,160ns)}
C {devices/lab_pin.sym} -930 -650 1 0 {name=l101 sig_type=std_logic lab=x0_bar_S}
C {devices/gnd.sym} -900 -520 0 0 {name=l108 lab=GND}
C {devices/gnd.sym} -930 -550 0 0 {name=l109 lab=GND}
C {devices/lab_pin.sym} -900 -620 1 0 {name=l110 sig_type=std_logic lab=x0_S}
C {devices/lab_pin.sym} -870 -590 1 0 {name=l111 sig_type=std_logic lab=x1_bar_S}
C {devices/gnd.sym} -840 -470 0 0 {name=l112 lab=GND}
C {devices/gnd.sym} -870 -490 0 0 {name=l113 lab=GND}
C {devices/lab_pin.sym} -840 -560 1 0 {name=l114 sig_type=std_logic lab=x1_S}
C {devices/lab_pin.sym} -810 -530 1 0 {name=l115 sig_type=std_logic lab=x2_bar_S}
C {devices/gnd.sym} -780 -400 0 0 {name=l116 lab=GND}
C {devices/gnd.sym} 550 -390 0 0 {name=l117 lab=GND}
C {devices/lab_pin.sym} 580 -460 1 0 {name=l118 sig_type=std_logic lab=x2_S}
C {devices/lab_pin.sym} 610 -430 1 0 {name=l119 sig_type=std_logic lab=x3_bar_S}
C {devices/gnd.sym} 640 -300 0 0 {name=l120 lab=GND}
C {devices/gnd.sym} 610 -330 0 0 {name=l121 lab=GND}
C {devices/lab_pin.sym} 640 -400 1 0 {name=l122 sig_type=std_logic lab=x3_S}
C {devices/vsource.sym} 430 -560 0 0 {name=Vin25 value=pulse(0,1.8,1ns,50ps,50ps,100ns,200ns)}
C {devices/vsource.sym} 460 -530 0 0 {name=Vin26 value=pulse(1.8,0,1ns,50ps,50ps,100ns,200ns)}
C {devices/vsource.sym} 490 -500 0 0 {name=Vin27 value=pulse(0,1.8,1ns,50ps,50ps,200ns,400ns)}
C {devices/vsource.sym} 520 -470 0 0 {name=Vin28 value=pulse(1.8,0,1ns,50ps,50ps,200ns,400ns)}
C {devices/vsource.sym} 550 -440 0 0 {name=Vin29 value=pulse(0,1.8,1ns,50ps,50ps,400ns,800ns)}
C {devices/vsource.sym} 580 -410 0 0 {name=Vin30 value=pulse(1.8,0,1ns,50ps,50ps,400ns,800ns)}
C {devices/vsource.sym} 610 -380 0 0 {name=Vin31 value=pulse(0,1.8,1ns,50ps,50ps,800ns,1600ns)}
C {devices/vsource.sym} 640 -350 0 0 {name=Vin32 value=pulse(1.8,0,1ns,50ps,50ps,800ns,1600ns)}
C {devices/lab_pin.sym} 430 -610 1 0 {name=l123 sig_type=std_logic lab=x0_bar_S}
C {devices/gnd.sym} 460 -480 0 0 {name=l134 lab=GND}
C {devices/gnd.sym} 430 -510 0 0 {name=l135 lab=GND}
C {devices/lab_pin.sym} 460 -580 1 0 {name=l136 sig_type=std_logic lab=x0_S}
C {devices/lab_pin.sym} 490 -550 1 0 {name=l137 sig_type=std_logic lab=x1_bar_S}
C {devices/gnd.sym} 520 -430 0 0 {name=l138 lab=GND}
C {devices/gnd.sym} 490 -450 0 0 {name=l139 lab=GND}
C {devices/lab_pin.sym} 520 -520 1 0 {name=l140 sig_type=std_logic lab=x1_S}
C {devices/lab_pin.sym} 550 -490 1 0 {name=l141 sig_type=std_logic lab=x2_bar_S}
C {devices/gnd.sym} 580 -360 0 0 {name=l142 lab=GND}
C {devices/lab_pin.sym} 1480 -1460 0 0 {name=l143 sig_type=std_logic lab=x0_S}
C {devices/lab_pin.sym} 1480 -1440 0 0 {name=l144 sig_type=std_logic lab=x0_bar_S}
C {devices/lab_pin.sym} 1480 -1340 0 0 {name=l145 sig_type=std_logic lab=x3_S}
C {devices/lab_pin.sym} 1480 -1320 0 0 {name=l146 sig_type=std_logic lab=x3_bar_S}
C {devices/lab_pin.sym} 1480 -1400 0 0 {name=l147 sig_type=std_logic lab=x1_bar_S}
C {devices/lab_pin.sym} 1480 -1420 0 0 {name=l148 sig_type=std_logic lab=x1_S}
C {devices/lab_pin.sym} 1480 -1360 0 0 {name=l149 sig_type=std_logic lab=x2_bar_S}
C {devices/lab_pin.sym} 1480 -1380 0 0 {name=l150 sig_type=std_logic lab=x2_S}
C {devices/lab_pin.sym} 1830 -1480 2 0 {name=l151 sig_type=std_logic lab=s1}
C {devices/gnd.sym} 1800 -1460 0 0 {name=l152 lab=GND}
C {devices/lab_pin.sym} 1480 -1480 0 0 {name=l153 sig_type=std_logic lab=VDD}
C {CMOS_s1.sym} 1650 -1400 0 0 {name=x11}
C {devices/gnd.sym} 2650 710 0 0 {name=l154 lab=GND}
C {devices/lab_pin.sym} 1410 660 0 0 {name=l155 sig_type=std_logic lab=VDD}
C {devices/lab_pin.sym} 1410 850 0 0 {name=l156 sig_type=std_logic lab=VDD}
C {devices/lab_pin.sym} 1940 590 0 0 {name=l157 sig_type=std_logic lab=VDD}
C {devices/lab_pin.sym} 2330 670 0 0 {name=l158 sig_type=std_logic lab=VDD}
C {devices/lab_pin.sym} 1940 760 0 0 {name=l159 sig_type=std_logic lab=VDD}
C {devices/lab_pin.sym} 1390 510 0 0 {name=l160 sig_type=std_logic lab=VDD}
C {devices/lab_pin.sym} 2670 670 2 0 {name=l161 sig_type=std_logic lab=s2_flat}
C {devices/lab_pin.sym} 1390 530 0 0 {name=l162 sig_type=std_logic lab=x3_S}
C {devices/lab_pin.sym} 1390 550 0 0 {name=l163 sig_type=std_logic lab=x3_bar_S}
C {devices/lab_pin.sym} 1390 590 0 0 {name=l164 sig_type=std_logic lab=x2_bar_S}
C {devices/lab_pin.sym} 1390 570 0 0 {name=l165 sig_type=std_logic lab=x2_S}
C {devices/lab_pin.sym} 1390 700 0 0 {name=l166 sig_type=std_logic lab=x1_bar_S}
C {devices/lab_pin.sym} 1390 680 0 0 {name=l167 sig_type=std_logic lab=x1_S}
C {devices/lab_pin.sym} 1410 720 0 0 {name=l168 sig_type=std_logic lab=x0_S}
C {devices/lab_pin.sym} 1410 740 0 0 {name=l169 sig_type=std_logic lab=x0_bar_S}
C {devices/lab_pin.sym} 1410 870 0 0 {name=l170 sig_type=std_logic lab=x3_bar_S}
C {devices/lab_pin.sym} 1410 890 0 0 {name=l171 sig_type=std_logic lab=x1_S}
C {devices/lab_pin.sym} 1410 910 0 0 {name=l172 sig_type=std_logic lab=x0_S}
C {devices/lab_pin.sym} 1410 930 0 0 {name=l173 sig_type=std_logic lab=x2_S}
C {devices/lab_pin.sym} 1940 630 0 0 {name=l174 sig_type=std_logic lab=x1_bar_S}
C {devices/lab_pin.sym} 1940 800 0 0 {name=l175 sig_type=std_logic lab=x2_bar_S}
C {devices/gnd.sym} 2260 630 0 0 {name=l176 lab=GND}
C {devices/gnd.sym} 2260 800 0 0 {name=l177 lab=GND}
C {devices/gnd.sym} 1730 700 0 0 {name=l178 lab=GND}
C {devices/gnd.sym} 1730 550 0 0 {name=l179 lab=GND}
C {devices/gnd.sym} 1730 890 0 0 {name=l180 lab=GND}
C {CMOS_3in_OR.sym} 2500 700 0 0 {name=x12}
C {CMOS_4in_AND.sym} 1580 890 0 0 {name=x13}
C {CMOS_AND.sym} 2110 780 0 0 {name=x14}
C {CMOS_AND.sym} 2110 610 0 0 {name=x15}
C {CMOS_XNOR.sym} 1580 550 0 0 {name=x16}
C {CMOS_XOR.sym} 1580 700 0 0 {name=x17}
C {devices/gnd.sym} -450 -830 0 0 {name=l181 lab=GND}
C {devices/lab_pin.sym} -420 -900 1 0 {name=l182 sig_type=std_logic lab=x2_S}
C {devices/lab_pin.sym} -390 -870 1 0 {name=l183 sig_type=std_logic lab=x3_bar_S}
C {devices/gnd.sym} -360 -740 0 0 {name=l184 lab=GND}
C {devices/gnd.sym} -390 -770 0 0 {name=l185 lab=GND}
C {devices/lab_pin.sym} -360 -840 1 0 {name=l186 sig_type=std_logic lab=x3_S}
C {devices/vsource.sym} -570 -1000 0 0 {name=Vin33 value=pulse(0,1.8,1n,50ps,50ps,20ns,40ns)}
C {devices/vsource.sym} -540 -970 0 0 {name=Vin34 value=pulse(1.8,0,1n,50ps,50ps,20ns,40ns)}
C {devices/vsource.sym} -510 -940 0 0 {name=Vin35 value=pulse(0,1.8,1n,50ps,50ps,40ns,80ns)}
C {devices/vsource.sym} -480 -910 0 0 {name=Vin36 value=pulse(1.8,0,1n,50ps,50ps,40ns,80ns)}
C {devices/vsource.sym} -450 -880 0 0 {name=Vin37 value=pulse(0,1.8,1n,50ps,50ps,80ns,160ns)}
C {devices/vsource.sym} -420 -850 0 0 {name=Vin38 value=pulse(1.8,0,1n,50ps,50ps,80ns,160ns)}
C {devices/vsource.sym} -390 -820 0 0 {name=Vin39 value=pulse(0,1.8,1n,50ps,50ps,160ns,320ns)}
C {devices/vsource.sym} -360 -790 0 0 {name=Vin40 value=pulse(1.8,0,1n,50ps,50ps,160ns,320ns)}
C {devices/lab_pin.sym} -570 -1050 1 0 {name=l187 sig_type=std_logic lab=x0_bar_S}
C {devices/gnd.sym} -540 -920 0 0 {name=l188 lab=GND}
C {devices/gnd.sym} -570 -950 0 0 {name=l189 lab=GND}
C {devices/lab_pin.sym} -540 -1020 1 0 {name=l190 sig_type=std_logic lab=x0_S}
C {devices/lab_pin.sym} -510 -990 1 0 {name=l191 sig_type=std_logic lab=x1_bar_S}
C {devices/gnd.sym} -480 -870 0 0 {name=l192 lab=GND}
C {devices/gnd.sym} -510 -890 0 0 {name=l193 lab=GND}
C {devices/lab_pin.sym} -480 -960 1 0 {name=l194 sig_type=std_logic lab=x1_S}
C {devices/lab_pin.sym} -450 -930 1 0 {name=l195 sig_type=std_logic lab=x2_bar_S}
C {devices/gnd.sym} -420 -800 0 0 {name=l196 lab=GND}
C {devices/gnd.sym} -70 -840 0 0 {name=l197 lab=GND}
C {devices/lab_pin.sym} -40 -910 1 0 {name=l198 sig_type=std_logic lab=x2_S}
C {devices/lab_pin.sym} -10 -880 1 0 {name=l199 sig_type=std_logic lab=x3_bar_S}
C {devices/gnd.sym} 20 -750 0 0 {name=l200 lab=GND}
C {devices/gnd.sym} -10 -780 0 0 {name=l201 lab=GND}
C {devices/lab_pin.sym} 20 -850 1 0 {name=l202 sig_type=std_logic lab=x3_S}
C {devices/vsource.sym} -190 -1010 0 0 {name=Vin41 value=pulse(0,1.8,1n,50ps,50ps,80ns,160ns)}
C {devices/vsource.sym} -160 -980 0 0 {name=Vin42 value=pulse(1.8,0,1n,50ps,50ps,80ns,160ns)}
C {devices/vsource.sym} -130 -950 0 0 {name=Vin43 value=pulse(0,1.8,1n,50ps,50ps,160ns,320ns)}
C {devices/vsource.sym} -100 -920 0 0 {name=Vin44 value=pulse(1.8,0,1n,50ps,50ps,160ns,320ns)}
C {devices/vsource.sym} -70 -890 0 0 {name=Vin45 value=pulse(0,1.8,1n,50ps,50ps,320ns,640ns)}
C {devices/vsource.sym} -40 -860 0 0 {name=Vin46 value=pulse(1.8,0,1n,50ps,50ps,320ns,640ns)}
C {devices/vsource.sym} -10 -830 0 0 {name=Vin47 value=pulse(0,1.8,1n,50ps,50ps,640ns,1280ns)}
C {devices/vsource.sym} 20 -800 0 0 {name=Vin48 value=pulse(1.8,0,1n,50ps,50ps,640ns,1280ns)}
C {devices/lab_pin.sym} -190 -1060 1 0 {name=l203 sig_type=std_logic lab=x0_bar_S}
C {devices/gnd.sym} -160 -930 0 0 {name=l204 lab=GND}
C {devices/gnd.sym} -190 -960 0 0 {name=l205 lab=GND}
C {devices/lab_pin.sym} -160 -1030 1 0 {name=l206 sig_type=std_logic lab=x0_S}
C {devices/lab_pin.sym} -130 -1000 1 0 {name=l207 sig_type=std_logic lab=x1_bar_S}
C {devices/gnd.sym} -100 -880 0 0 {name=l208 lab=GND}
C {devices/gnd.sym} -130 -900 0 0 {name=l209 lab=GND}
C {devices/lab_pin.sym} -100 -970 1 0 {name=l212 sig_type=std_logic lab=x1_S}
C {devices/lab_pin.sym} -70 -940 1 0 {name=l213 sig_type=std_logic lab=x2_bar_S}
C {devices/gnd.sym} -40 -810 0 0 {name=l214 lab=GND}
C {devices/gnd.sym} -450 -400 0 0 {name=l215 lab=GND}
C {devices/lab_pin.sym} -420 -470 1 0 {name=l216 sig_type=std_logic lab=x2_S}
C {devices/lab_pin.sym} -390 -440 1 0 {name=l217 sig_type=std_logic lab=x3_bar_S}
C {devices/gnd.sym} -360 -310 0 0 {name=l218 lab=GND}
C {devices/gnd.sym} -390 -340 0 0 {name=l219 lab=GND}
C {devices/lab_pin.sym} -360 -410 1 0 {name=l220 sig_type=std_logic lab=x3_S}
C {devices/vsource.sym} -570 -570 0 0 {name=Vin49 value=pulse(0,1.8,1n,50ps,50ps,40ns,80ns)}
C {devices/vsource.sym} -540 -540 0 0 {name=Vin50 value=pulse(1.8,0,1n,50ps,50ps,40ns,80ns)}
C {devices/vsource.sym} -510 -510 0 0 {name=Vin51 value=pulse(0,1.8,1n,50ps,50ps,80ns,160ns)}
C {devices/vsource.sym} -480 -480 0 0 {name=Vin52 value=pulse(1.8,0,1n,50ps,50ps,80ns,160ns)}
C {devices/vsource.sym} -450 -450 0 0 {name=Vin53 value=pulse(0,1.8,1n,50ps,50ps,160ns,320ns)}
C {devices/vsource.sym} -420 -420 0 0 {name=Vin54 value=pulse(1.8,0,1n,50ps,50ps,160ns,320ns)}
C {devices/vsource.sym} -390 -390 0 0 {name=Vin55 value=pulse(0,1.8,1n,50ps,50ps,320ns,640ns)}
C {devices/vsource.sym} -360 -360 0 0 {name=Vin56 value=pulse(1.8,0,1n,50ps,50ps,320ns,640ns)}
C {devices/lab_pin.sym} -570 -620 1 0 {name=l221 sig_type=std_logic lab=x0_bar_S}
C {devices/gnd.sym} -540 -490 0 0 {name=l228 lab=GND}
C {devices/gnd.sym} -570 -520 0 0 {name=l229 lab=GND}
C {devices/lab_pin.sym} -540 -590 1 0 {name=l230 sig_type=std_logic lab=x0_S}
C {devices/lab_pin.sym} -510 -560 1 0 {name=l231 sig_type=std_logic lab=x1_bar_S}
C {devices/gnd.sym} -480 -440 0 0 {name=l232 lab=GND}
C {devices/gnd.sym} -510 -460 0 0 {name=l233 lab=GND}
C {devices/lab_pin.sym} -480 -530 1 0 {name=l234 sig_type=std_logic lab=x1_S}
C {devices/lab_pin.sym} -450 -500 1 0 {name=l235 sig_type=std_logic lab=x2_bar_S}
C {devices/gnd.sym} -420 -370 0 0 {name=l236 lab=GND}
C {devices/gnd.sym} -810 50 0 0 {name=l237 lab=GND}
C {devices/lab_pin.sym} -780 -20 1 0 {name=l238 sig_type=std_logic lab=x2_S}
C {devices/lab_pin.sym} -750 10 1 0 {name=l239 sig_type=std_logic lab=x3_bar_S}
C {devices/gnd.sym} -720 140 0 0 {name=l240 lab=GND}
C {devices/gnd.sym} -750 110 0 0 {name=l241 lab=GND}
C {devices/lab_pin.sym} -720 40 1 0 {name=l242 sig_type=std_logic lab=x3_S}
C {devices/vsource.sym} -930 -120 0 0 {name=Vin57 value=pulse(0,1.8,1ns,100ps,100ps,10ns,20ns)}
C {devices/vsource.sym} -900 -90 0 0 {name=Vin58 value=pulse(1.8,0,1ns,100ps,100ps,10ns,20ns)}
C {devices/vsource.sym} -870 -60 0 0 {name=Vin59 value=pulse(0,1.8,1ns,100ps,100ps,20ns,40ns)}
C {devices/vsource.sym} -840 -30 0 0 {name=Vin60 value=pulse(1.8,0,1ns,100ps,100ps,20ns,40ns)}
C {devices/vsource.sym} -810 0 0 0 {name=Vin61 value=pulse(0,1.8,1ns,100ps,100ps,40ns,80ns)}
C {devices/vsource.sym} -780 30 0 0 {name=Vin62 value=pulse(1.8,0,1ns,100ps,100ps,40ns,80ns)}
C {devices/vsource.sym} -750 60 0 0 {name=Vin63 value=pulse(0,1.8,1ns,100ps,100ps,80ns,160ns)}
C {devices/vsource.sym} -720 90 0 0 {name=Vin64 value=pulse(1.8,0,1ns,100ps,100ps,80ns,160ns)}
C {devices/lab_pin.sym} -930 -170 1 0 {name=l243 sig_type=std_logic lab=x0_bar_S}
C {devices/gnd.sym} -900 -40 0 0 {name=l244 lab=GND}
C {devices/gnd.sym} -930 -70 0 0 {name=l245 lab=GND}
C {devices/lab_pin.sym} -900 -140 1 0 {name=l246 sig_type=std_logic lab=x0_S}
C {devices/lab_pin.sym} -870 -110 1 0 {name=l247 sig_type=std_logic lab=x1_bar_S}
C {devices/gnd.sym} -840 10 0 0 {name=l248 lab=GND}
C {devices/gnd.sym} -870 -10 0 0 {name=l249 lab=GND}
C {devices/lab_pin.sym} -840 -80 1 0 {name=l250 sig_type=std_logic lab=x1_S}
C {devices/lab_pin.sym} -810 -50 1 0 {name=l251 sig_type=std_logic lab=x2_bar_S}
C {devices/gnd.sym} -780 80 0 0 {name=l252 lab=GND}
C {devices/gnd.sym} 60 60 0 0 {name=l253 lab=GND}
C {devices/lab_pin.sym} 90 -10 1 0 {name=l254 sig_type=std_logic lab=x2_S}
C {devices/lab_pin.sym} 120 20 1 0 {name=l255 sig_type=std_logic lab=x3_bar_S}
C {devices/gnd.sym} 150 150 0 0 {name=l256 lab=GND}
C {devices/gnd.sym} 120 120 0 0 {name=l257 lab=GND}
C {devices/lab_pin.sym} 150 50 1 0 {name=l258 sig_type=std_logic lab=x3_S}
C {devices/vsource.sym} -60 -110 0 0 {name=Vin65 value=pulse(0,1.8,80ns,50ps,50ps,80ns,160ns)}
C {devices/vsource.sym} -30 -80 0 0 {name=Vin66 value=pulse(1.8,0,80ns,50ps,50ps,80ns,160ns)}
C {devices/vsource.sym} 0 -50 0 0 {name=Vin67 value=pulse(0,1.8,80ns,50ps,50ps,160ns,320ns)}
C {devices/vsource.sym} 30 -20 0 0 {name=Vin68 value=pulse(1.8,0,80ns,50ps,50ps,160ns,320ns)}
C {devices/vsource.sym} 60 10 0 0 {name=Vin69 value=pulse(0,1.8,80ns,50ps,50ps,320ns,640ns)}
C {devices/vsource.sym} 90 40 0 0 {name=Vin70 value=pulse(1.8,0,80ns,50ps,50ps,320ns,640ns)}
C {devices/vsource.sym} 120 70 0 0 {name=Vin71 value=pulse(0,1.8,80ns,50ps,50ps,640ns,1280ns)}
C {devices/vsource.sym} 150 100 0 0 {name=Vin72 value=pulse(1.8,0,80ns,50ps,50ps,640ns,1280ns)}
C {devices/lab_pin.sym} -60 -160 1 0 {name=l259 sig_type=std_logic lab=x0_bar_S}
C {devices/gnd.sym} -30 -30 0 0 {name=l260 lab=GND}
C {devices/gnd.sym} -60 -60 0 0 {name=l261 lab=GND}
C {devices/lab_pin.sym} -30 -130 1 0 {name=l262 sig_type=std_logic lab=x0_S}
C {devices/lab_pin.sym} 0 -100 1 0 {name=l263 sig_type=std_logic lab=x1_bar_S}
C {devices/gnd.sym} 30 20 0 0 {name=l264 lab=GND}
C {devices/gnd.sym} 0 0 0 0 {name=l265 lab=GND}
C {devices/lab_pin.sym} 30 -70 1 0 {name=l266 sig_type=std_logic lab=x1_S}
C {devices/lab_pin.sym} 60 -40 1 0 {name=l267 sig_type=std_logic lab=x2_bar_S}
C {devices/gnd.sym} 90 90 0 0 {name=l268 lab=GND}
C {devices/gnd.sym} 2140 -1070 0 0 {name=l269 lab=GND}
C {devices/lab_pin.sym} 2270 -1150 2 0 {name=l270 sig_type=std_logic lab=s0_flat}
C {devices/lab_pin.sym} 2270 -1130 2 0 {name=l271 sig_type=std_logic lab=s1_flat}
C {devices/lab_pin.sym} 2270 -1110 2 0 {name=l272 sig_type=std_logic lab=s2_flat}
C {devices/lab_pin.sym} 2270 -1090 2 0 {name=l273 sig_type=std_logic lab=s3_flat}
C {devices/capa.sym} 2150 -1220 2 0 {name=C9
m=1
value=20f
footprint=1206
device="ceramic capacitor"}
C {devices/gnd.sym} 2150 -1250 2 0 {name=l274 lab=GND}
C {devices/capa.sym} 2180 -1220 2 0 {name=C10
m=1
value=20f
footprint=1206
device="ceramic capacitor"}
C {devices/gnd.sym} 2180 -1250 2 0 {name=l275 lab=GND}
C {devices/capa.sym} 2210 -1220 2 0 {name=C11
m=1
value=20f
footprint=1206
device="ceramic capacitor"}
C {devices/gnd.sym} 2210 -1250 2 0 {name=l276 lab=GND}
C {devices/capa.sym} 2240 -1220 2 0 {name=C12
m=1
value=20f
footprint=1206
device="ceramic capacitor"}
C {devices/gnd.sym} 2240 -1250 2 0 {name=l277 lab=GND}
C {devices/code_shown.sym} 2680 -1430 0 0 {name=SPICE only_toplevel=false 
value= ".lib /research/pdk/open_pdks/share/pdk/sky130A/libs.tech/ngspice/sky130.lib.spice tt
**.include ~/magic_layout_stuff/CMOS_PRESENT80_R1.spice
.include ~/magic_layout_stuff/CMOS_PRESENT80_R1_flat.spice
.option method=gear MAXORD=3
.control
save all
tran 0.02n 14.4u
**plot v(s0_norm) v(s1_norm) v(s2_norm) v(s3_norm)
**plot v(s0_flat) v(s1_flat) v(s2_flat) v(s3_flat)
plot v(x0_S)
plot v(x1_S)
plot v(x2_S)
plot v(x3_S)
**plot v(s0_norm) 
**plot v(s1_norm) 
**plot v(s2_norm) 
**plot v(s3_norm)
plot v(s0_flat) 
plot v(s1_flat) 
plot v(s2_flat) 
plot v(s3_flat)
**plot v(CLK0_S) v(CLK1_S) v(CLK2_S) v(CLK3_S)
**plot v(XOR0_S) v(XOR1_S) v(XOR2_S) v(XOR3_S)
**plot v(k0_S) v(k1_S) v(k2_S) v(k3_S)
**plot v(s0_flat)
**plot v(s1_flat)
**plot v(s2_flat)
**plot v(s3_flat)
**plot v(s0_bar_norm) v(s1_bar_norm) v(s2_bar_norm) v(s3_bar_norm)
**plot v(s0_bar_flat) v(s1_bar_flat) v(s2_bar_flat) v(s3_bar_flat)
let Pinst = v(VDD)*v9#branch
plot v9#branch
plot Pinst
**let Pinst_CLK0_CLK3 = (v(CLK0_S)*i(vclk18))+(v(CLK1_S)*i(vclk22))+(v(CLK2_S)*i(vclk23))+(v(CLK3_S)*i(vclk24))
**let Pinst_CLK0_CLK2_Dis0_Dis2 = (v(CLK0)*i(vclk0))+(v(Dis0)*i(Vdis0))+(v(CLK1)*i(vclk1))+(v(Dis1)*i(Vdis1))+(v(CLK2)*i(vclk2))+(v(Dis2)*i(Vdis2))
**plot Pinst_CLK0
**plot Pinst_CLK0_CLK3
**wrdata EESPFAL_PRESENT80R1_CLKs.raw v(CLK0_S) v(CLK1_S) v(CLK2_S) v(CLK3_S)
**wrdata CMOS_PRESENT80R1_X_inputs.raw v(XOR0_S) v(XOR1_S) v(XOR2_S) v(XOR3_S)
**wrdata CMOS_PRESENT80R1_K_inputs.raw v(k0_S) v(k1_S) v(k2_S) v(k3_S)
**wrdata CMOS_PRESENT80R1_InstPWR_K0_10MHz.csv Pinst
**wrdata CMOS_PRESENT80R1_InstPWR_K0_100MHz.csv Pinst
**wrdata CMOS_IPWR_K0_100MHz_0p02ns_14p4ns.csv Pinst
**wrdata CMOS_IPWR_K5_100MHz_0p02ns_14p4ns.csv Pinst
**wrdata CMOS_IPWR_K0_100MHz_0p02ns_14p4ns_10nsDelay.csv Pinst
**wrdata CMOS_IPWR_K0_25MHz_0p02ns_14p4ns_80nsDelay.csv Pinst
**wrdata CMOS_IPWR_K0_50MHz_0p02ns_14p4ns.csv Pinst
**wrdata CMOS_IPWR_K0_25MHz_0p02ns_14p4ns.csv Pinst
**wrdata CMOS_IPWR_K0_12p5MHz_0p02ns_14p4ns.csv Pinst
**wrdata CMOS_IPWR_K0_12p5MHz_0p02ns_14p4ns_80nsDelay.csv Pinst
**wrdata CMOS_IPWR_K7_12p5MHz_0p02ns_14p4ns_80nsDelay.csv Pinst
**wrdata CMOS_PRESENT80R1_InstPWR_GEAR6_16u.csv Pinst FAILED
**wrdata EESPFAL_PRESENT80_R1.raw v(s0_norm) v(s1_norm) v(s2_norm) v(s3_norm) v(s0_bar_norm) v(s1_bar_norm) v(s2_bar_norm) v(s3_bar_norm)
**wrdata EESPFAL_PRESENT80_R1_PEX.raw v(s0_flat) v(s1_flat) v(s2_flat) v(s3_flat) v(s0_bar_flat) v(s1_bar_flat) v(s2_bar_flat) v(s3_bar_flat) 
**wrdata EESPFAL_PRESENT80_R1.csv v(s0_norm) v(s1_norm) v(s2_norm) v(s3_norm) v(s0_bar_norm) v(s1_bar_norm) v(s2_bar_norm) v(s3_bar_norm)
**wrdata EESPFAL_PRESENT80_R1_PEX.csv v(s0_flat) v(s1_flat) v(s2_flat) v(s3_flat) v(s0_bar_flat) v(s1_bar_flat) v(s2_bar_flat) v(s3_bar_flat)
**wrdata EESPFAL_PRESENT80_R1_PEX_PWR.raw Pinst_CLK0_CLK3
**wrdata EESPFAL_PRESENT80_R1_PEX_PWR.csv Pinst_CLK0_CLK3
**wrdata EESPFAL_PRESENT80_R1.raw
.endc
"}
C {devices/lab_pin.sym} -750 -1690 1 0 {name=l278 sig_type=std_logic lab=x2_S}
C {devices/lab_pin.sym} -790 -1490 1 0 {name=l279 sig_type=std_logic lab=x3_bar_S}
C {devices/lab_pin.sym} -750 -1450 1 0 {name=l280 sig_type=std_logic lab=x3_S}
C {devices/lab_pin.sym} -910 -1810 1 0 {name=l281 sig_type=std_logic lab=x0_bar_S}
C {devices/lab_pin.sym} -910 -1580 1 0 {name=l282 sig_type=std_logic lab=x1_bar_S}
C {devices/lab_pin.sym} -870 -1540 1 0 {name=l283 sig_type=std_logic lab=x1_S}
C {devices/lab_pin.sym} -790 -1730 1 0 {name=l284 sig_type=std_logic lab=x2_bar_S}
C {devices/vsource.sym} -910 -1760 0 0 {name=Vx1 value=pulse('v1','v2','delay','rt','ft','pw_x0','period_x0')}
C {devices/gnd.sym} -910 -1710 0 0 {name=l285 lab=GND}
C {devices/vsource.sym} -880 -1730 0 0 {name=Vx2 value=pulse('v2','v1','delay','rt','ft','pw_x0','period_x0')}
C {devices/lab_pin.sym} -880 -1780 1 0 {name=l286 sig_type=std_logic lab=x0_S}
C {devices/gnd.sym} -880 -1680 0 0 {name=l287 lab=GND}
C {devices/vsource.sym} -910 -1530 0 0 {name=Vx3 value=pulse('v1','v2','delay','rt','ft','pw_x1','period_x1')}
C {devices/vsource.sym} -870 -1500 0 0 {name=Vx4 value=pulse('v2','v1','delay','rt','ft','pw_x1','period_x1')}
C {devices/gnd.sym} -910 -1480 0 0 {name=l288 lab=GND}
C {devices/gnd.sym} -870 -1450 0 0 {name=l289 lab=GND}
C {devices/vsource.sym} -790 -1680 0 0 {name=Vx5 value=pulse('v1','v2','delay','rt','ft','pw_x2','period_x2')}
C {devices/vsource.sym} -750 -1650 0 0 {name=Vx6 value=pulse('v2','v1','delay','rt','ft','pw_x2','period_x2')}
C {devices/gnd.sym} -790 -1630 0 0 {name=l290 lab=GND}
C {devices/gnd.sym} -750 -1600 0 0 {name=l291 lab=GND}
C {devices/vsource.sym} -790 -1440 0 0 {name=Vx7 value=pulse('v1','v2','delay','rt','ft','pw_x3','period_x3')}
C {devices/vsource.sym} -750 -1410 0 0 {name=Vx8 value=pulse('v2','v1','delay','rt','ft','pw_x3','period_x3')}
C {devices/gnd.sym} -790 -1390 0 0 {name=l292 lab=GND}
C {devices/gnd.sym} -750 -1360 0 0 {name=l293 lab=GND}
C {devices/code_shown.sym} 2970 -150 0 0 {name=SPICE1 only_toplevel=false 
value= ".lib /research/pdk/open_pdks/share/pdk/sky130A/libs.tech/ngspice/sky130.lib.spice tt
**.include ~/magic_layout_stuff/CMOS_PRESENT80_R1.spice
**.include ~/magic_layout_stuff/CMOS_PRESENT80_R1_flat.spice
*.param v1='0' v2='1.8' delay='-1n' rt='50p' ft='50p' pw_x0='40n' period_x0='80n' pw_x1='80n' period_x1='160n' pw_x2='160n' period_x2='320n' pw_x3='320n' period_x3='640n'
.param v0 ='0' v0_bar ='1.8' v1 ='0' v1_bar ='1.8' v2 ='0' v2_bar ='1.8' v3 ='0' v3_bar ='1.8'
.option method=gear 
.control
set tstart=0
set tstop=80n
let index=0
let index2=0
let start = $tstart
let stop = $tstop
let start_r2 = $tstop*200
let stop_r2 = ($tstop*200)+80n
*tran 0.1n 10u
*set v1_n = 0 v2_n = 1.8 delay_n = 0 rt_n = 50p ft_n = 50p 
*set pw_x0n = 40n period_x0n = 80n pw_x1n = 80n period_x1n = 160n 
*set pw_x2n = 160n period_x2n = 320n pw_x3n = 320n period_x3n = 640n

set value = 5
echo stuff

*alter Vx0 = 1.8
*plot v(s0_norm)
*snsave testfile.snap
let curr_time = index*80n
*stop when time =$&curr_time
*tran 1n 2u 0 1n
*alter Vx0 = 0
*delete 1
*let curr_time = 160n
*stop when time = $&curr_time
*echo $&curr_time
*echo start loop

while curr_time < 240n
	let index=index+1	
	set  value = $&index 
	*let trantime = time[0]
	*echo $&trantime
	echo going into altering
	foreach bit_index 0 1 2 3
		*echo $bit_index
		*echo `./test.sh $value $bit_index`
		set bit = `./test.sh $value $bit_index`
		alter Vx$bit_index = '$bit ? 1.8 : 0'
		alter Vx`echo $bit_index`_bar = '$bit ? 0 : 1.8'
		*alter @Vx4[pulse] = [ $v1 $v2 $delay   ]
		*alterparam v$bit_index = '$bit ? 1.8 : 0'
		*alterparam v`echo $bit_index`_bar = '$bit ? 0 : 1.8'
	end
	*alter Vx0=1.8
	echo test stuff
	let curr_time=index*80n
	*delete $&index 
	stop when time=$&curr_time
	echo $&curr_time
	*break
	plot v(x0_s)
	if curr_time = 80ns
		tran 1n 2u 0 1n
	else 
		resume
	end
		
end

*let Pinst = v(VDD)*v9#branch
*wrdata K7_32u_50cycle.csv Pinst	
*while index < 401
*	let Pinst = v(VDD)*v9#branch	
	*plot Pinst
*	let lin-tstart = start
*	let lin-tstop = stop
*	let lin-tstep = 0.01n
*	linearize Pinst
	*plot v(pinst)
	*display
*	set appendwrite	
	*wrdata samp_interval_K0_32u_50cycle_minus1ns.csv Pinst
	*wrdata samp_interval_K1_32u_50cycle_minus1ns.csv Pinst
	*wrdata samp_interval_K2_32u_50cycle_minus1ns.csv Pinst
	*wrdata samp_interval_K3_32u_50cycle_minus1ns.csv Pinst
	*wrdata samp_interval_K4_32u_50cycle_minus1ns.csv Pinst
	*wrdata samp_interval_K5_32u_50cycle_minus1ns.csv Pinst
	*wrdata samp_interval_K6_32u_50cycle_minus1ns.csv Pinst
	*wrdata samp_interval_K7_32u_50cycle_minus1ns.csv Pinst
	*wrdata samp_interval_K8_32u_50cycle_minus1ns.csv Pinst
	*wrdata samp_interval_K9_32u_50cycle_minus1ns.csv Pinst
	*wrdata samp_interval_K10_32u_50cycle_minus1ns.csv Pinst
	*wrdata samp_interval_K11_32u_50cycle_minus1ns.csv Pinst
	*wrdata samp_interval_K12_32u_50cycle_minus1ns.csv Pinst
	*wrdata samp_interval_K13_32u_50cycle_minus1ns.csv Pinst
	*wrdata samp_interval_K14_32u_50cycle_minus1ns.csv Pinst
	*wrdata samp_interval_K15_32u_50cycle_minus1ns.csv Pinst
*	*wrdata samp_interval_6p4u_10cycle.csv Pinst
*	let start = stop
*	let stop = stop+80n
*	let index = index + 1
*	*echo $plots
*	setplot tran1
*	destroy tran2 
*	*echo $plots
*end

*while index2 < 201
*	tran 0.7u 34u 0 1u
*	let Pinst = v(VDD)*v9#branch
*	let lin-tstart = start_r2 
*	let lin-tstop = stop_r2 
*	let lin-tstep = 1n
*	linearize Pinst
*	*plot Pinst
*	set appendwrite
*	wrdata samp_interval_32u_50cycle.csv Pinst
*	*wrdata samp_interval_6p4u_10cycle.csv Pinst
*	let start_r2 = stop_r2
*	let stop_r2 = stop_r2+80n
*	let index2 = index2 + 1
*end
.endc
"}
C {devices/code_shown.sym} 2630 -2500 0 0 {name=SPICE2 only_toplevel=false 
value= ".lib /research/pdk/open_pdks/share/pdk/sky130A/libs.tech/ngspice/sky130.lib.spice tt
**.include ~/magic_layout_stuff/CMOS_PRESENT80_R1.spice
**.include ~/magic_layout_stuff/CMOS_PRESENT80_R1_flat.spice
.param v0 ='0' v0_bar ='1.8' v1 ='0' v1_bar ='1.8' v2 ='0' v2_bar ='1.8' v3 ='0' v3_bar ='1.8'
.option method=gear 
.control
set tstart=0
*set tstop=0
let index=0
let index2=1
let wstart = $tstart
let wstop = 0n
let start_r2 = $tstop*200
let stop_r2 = ($tstop*200)+80n

set values_raw < circ_inputs.txt
compose values values $values_raw 
echo stuff

*let curr_time = index*40n

while index2 < length(values)
	let wstop = $&index2*40n
	stop when time=$&wstop
	let index2 = $&index2+1
	echo $&index2
end

*tran 1n 2u 0 1n
let tstop = length(values)*40n
while index < length(values)
		
	let value = values[$&index]
	echo $&value 
	echo going into altering
	foreach bit_index 0 1 2 3
		set bit = `./test.sh $&value $bit_index`
		alter Vx$bit_index = '$bit ? 1.8 : 0'
		alter Vx`echo $bit_index`_bar = '$bit ? 0 : 1.8'
	end
	echo test stuff
	let index=index+1
	if index = 1
		tran 1n $&tstop 0 1n
	else 	
		resume	
	end	
end
.endc
"}
C {devices/gnd.sym} 510 -1390 0 0 {name=l294 lab=GND}
C {devices/gnd.sym} 570 -1330 0 0 {name=l295 lab=GND}
C {devices/gnd.sym} 630 -1270 0 0 {name=l296 lab=GND}
C {devices/gnd.sym} 690 -1210 0 0 {name=l297 lab=GND}
C {devices/lab_pin.sym} 510 -1470 1 0 {name=l298 sig_type=std_logic lab=k0_S}
C {devices/lab_pin.sym} 570 -1410 1 0 {name=l299 sig_type=std_logic lab=k1_S}
C {devices/lab_pin.sym} 630 -1350 1 0 {name=l300 sig_type=std_logic lab=k2_S}
C {devices/lab_pin.sym} 690 -1290 1 0 {name=l301 sig_type=std_logic lab=k3_S}
C {devices/gnd.sym} 480 -1420 0 0 {name=l302 lab=GND}
C {devices/gnd.sym} 540 -1360 0 0 {name=l303 lab=GND}
C {devices/gnd.sym} 600 -1300 0 0 {name=l304 lab=GND}
C {devices/gnd.sym} 660 -1240 0 0 {name=l305 lab=GND}
C {devices/lab_pin.sym} 480 -1500 1 0 {name=l306 sig_type=std_logic lab=k0_bar_S}
C {devices/lab_pin.sym} 540 -1440 1 0 {name=l307 sig_type=std_logic lab=k1_bar_S}
C {devices/lab_pin.sym} 600 -1380 1 0 {name=l308 sig_type=std_logic lab=k2_bar_S}
C {devices/lab_pin.sym} 660 -1320 1 0 {name=l309 sig_type=std_logic lab=k3_bar_S}
C {devices/lab_pin.sym} 650 -1770 1 0 {name=l310 sig_type=std_logic lab=x2_S}
C {devices/lab_pin.sym} 680 -1740 1 0 {name=l311 sig_type=std_logic lab=x3_bar_S}
C {devices/lab_pin.sym} 710 -1710 1 0 {name=l312 sig_type=std_logic lab=x3_S}
C {devices/lab_pin.sym} 500 -1920 1 0 {name=l313 sig_type=std_logic lab=x0_bar_S}
C {devices/lab_pin.sym} 560 -1860 1 0 {name=l316 sig_type=std_logic lab=x1_bar_S}
C {devices/lab_pin.sym} 590 -1830 1 0 {name=l318 sig_type=std_logic lab=x1_S}
C {devices/lab_pin.sym} 620 -1800 1 0 {name=l320 sig_type=std_logic lab=x2_bar_S}
C {devices/vsource.sym} 510 -1420 0 0 {name=Vk0 value=1.8}
C {devices/vsource.sym} 540 -1390 0 0 {name=Vk1_bar value=0}
C {devices/vsource.sym} 570 -1360 0 0 {name=Vk1 value=1.8}
C {devices/vsource.sym} 630 -1300 0 0 {name=Vk2 value=0}
C {devices/gnd.sym} 500 -1820 0 0 {name=l322 lab=GND}
C {devices/lab_pin.sym} 530 -1890 1 0 {name=l327 sig_type=std_logic lab=x0_S}
C {devices/gnd.sym} 530 -1790 0 0 {name=l340 lab=GND}
C {devices/gnd.sym} 560 -1760 0 0 {name=l341 lab=GND}
C {devices/gnd.sym} 590 -1740 0 0 {name=l342 lab=GND}
C {devices/gnd.sym} 620 -1700 0 0 {name=l343 lab=GND}
C {devices/gnd.sym} 650 -1680 0 0 {name=l344 lab=GND}
C {devices/gnd.sym} 680 -1640 0 0 {name=l345 lab=GND}
C {devices/gnd.sym} 710 -1620 0 0 {name=l346 lab=GND}
C {devices/vsource.sym} 530 -1840 0 0 {name=Vx0 value=v0}
C {devices/vsource.sym} 500 -1870 0 0 {name=Vx0_bar value=v0_bar}
C {devices/vsource.sym} 620 -1750 0 0 {name=Vx2_bar value=v2_bar}
C {devices/vsource.sym} 650 -1720 0 0 {name=Vx9 value=v2}
C {devices/vsource.sym} 590 -1780 0 0 {name=Vx10 value=v1}
C {devices/vsource.sym} 560 -1810 0 0 {name=Vx1_bar value=v1_bar}
C {devices/vsource.sym} 680 -1690 0 0 {name=Vx3_bar value=v3_bar}
C {devices/vsource.sym} 710 -1660 0 0 {name=Vx11 value=v3}
C {devices/vsource.sym} 690 -1240 0 0 {name=Vk3 value=1.8}
C {devices/vsource.sym} 480 -1450 0 0 {name=Vk0_bar value=0}
C {devices/vsource.sym} 600 -1330 0 0 {name=Vk2_bar value=1.8}
C {devices/vsource.sym} 660 -1270 0 0 {name=Vk3_bar value=0}
